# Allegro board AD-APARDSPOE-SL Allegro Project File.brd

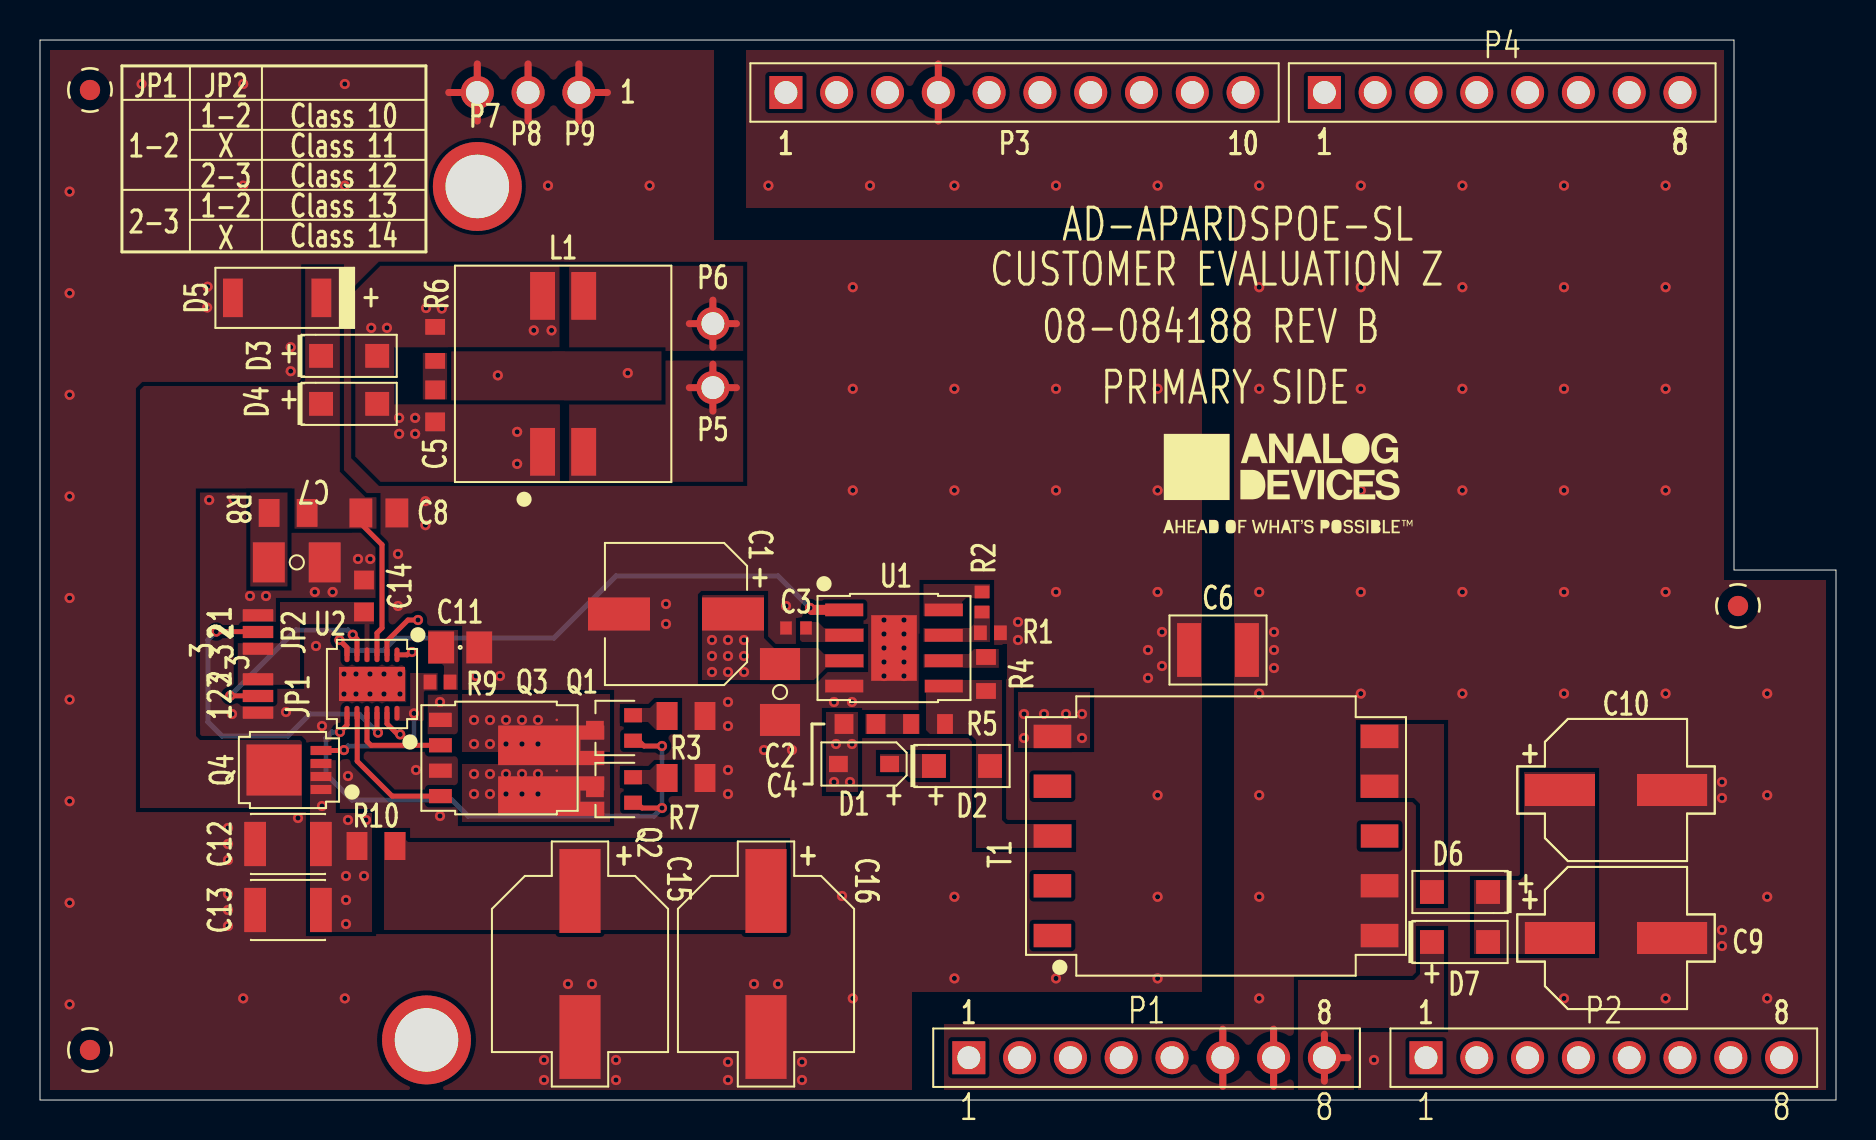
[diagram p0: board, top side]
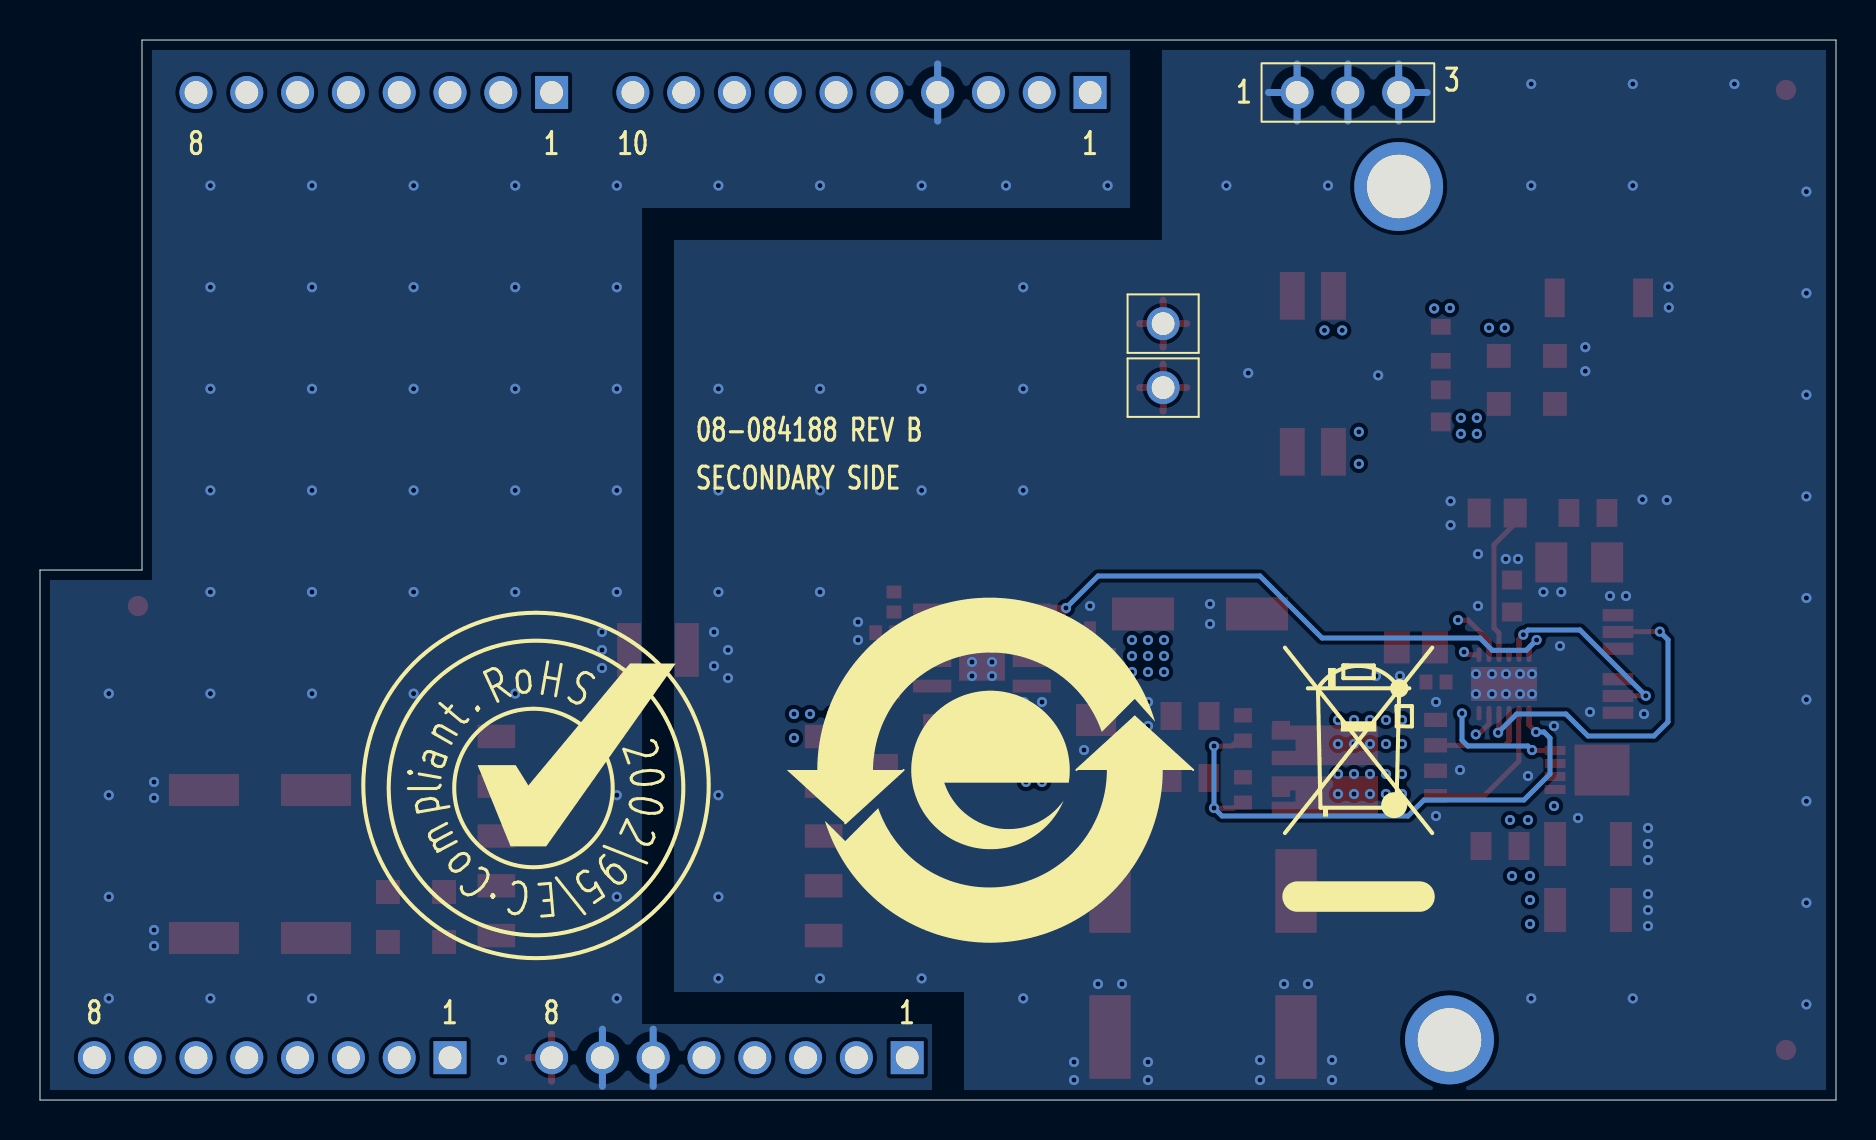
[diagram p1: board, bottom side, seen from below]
Outline 89.8 x 53 mm; copper layers: TOP, L2_GND, L3_PWR, BOTTOM. Coordinates in mm from the lower left corner of the outline.
Outline path: 0,53 84.7,53 84.7,26.5 89.8,26.5 89.8,0 0,0 0,53

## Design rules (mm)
constraint set DEFAULT: min track width 0.203

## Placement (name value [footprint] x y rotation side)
C1  22UF  [CPLSMSQ260H315]  31.8 24.3 180 top
C2  10UF  [C1206H71]  37 20.4 270 top
C3  1uF  [C0402]  37.8 23.6 180 top
C4  220pF  [C0603]  41 18.8 0 top
C5  0.047UF  [C0603]  19.76 34.71 270 top
C6  4.7NF  [C1210H67]  58.9 22.5 0 top
C7  150NF  [C1206H71]  12.84 26.88 0 top
C8  0.047uF  [C0805]  16.94 29.35 0 top
C9  220UF  [CPLSMSQ260H303]  78.8 8.1 0 top
C10  220UF  [CPLSMSQ260H303]  78.8 15.5 0 top
C11  0.022UF  [C0805H60]  21.01 22.63 180 top
C12  4.7uF  [C1210H87]  12.4 12.8 180 top
C13  4.7uF  [C1210H87]  12.4 9.5 180 top
C14  2.2uF  [C0603]  16.2 25.2 270 top
C15  33UF  [CPLSMSQ327H413]  27 6.8 270 top
C16  33UF  [CPLSMSQ327H413]  36.3 6.8 270 top
D1  BZX384-B51  [SOD323-2]  41.2 16.8 180 top
D2  PMEG10020AELRX  [SOD123F]  46.1 16.7 0 top
D3  PMEG10020AELRX  [SOD123F]  15.46 37.21 0 top
D4  PMEG10020AELRX  [SOD123F]  15.46 34.81 0 top
D5  PTVS58VP1UTP  [SOD128]  11.86 40.11 180 top
D6  PMEG10020AELRX  [SOD123F]  71 10.4 180 top
D7  PMEG10020AELRX  [SOD123F]  71 7.9 0 top
JP1  3PIN_SOLDER_JUMPER  [JPRSLD03]  10.9 20.2 90 top
JP2  3PIN_SOLDER_JUMPER  [JPRSLD03]  10.9 23.4 270 top
L1  68UH  [LSMSQ406H197]  26.16 36.31 90 top
NOREF  -  []  33.16 0 90 top
NOREF#2  -  [unnamed#2]  21.87 45.68 0 top
NOREF#3  -  [unnamed#2]  84.9 24.7 0 top
NOREF#4  -  [unnamed#2]  19.33 3 0 top
NOREF#5  -  [unnamed#2]  2.5 2.5 0 top
NOREF#6  -  []  -82.6 -106.1 0 top
NOREF#7  -  []  162.5 76.5 0 top
NOREF#8  -  []  62.1 30.8 0 top
NOREF#9  -  [unnamed#2]  2.5 50.5 0 top
NOREF#10  -  []  118 237.1 0 top
NOREF#11  -  []  89.8 0 90 top
NOREF#12  -  []  -82.6 -104.4 0 top
NOREF#13  -  []  -83 -106.1 0 top
NOREF#14  -  []  84.7 53 180 top
NOREF#15  -  []  0 49.82 0 top
NOREF#16  -  []  47.9 64 0 top
NOREF#17  -  []  0 53 270 top
NOREF#18  -  []  0 0 0 top
NOREF#19  -  []  65 15.6 180 bottom
NOREF#20  -  []  14.6 26.3 180 bottom
NOREF#21  -  []  42.3 16.5 180 bottom
NOREF#22  -  []  42.7 38.5 270 bottom
P1  ESQ-108-24-T-S  [CNTHFHDR1X8L820W95H545]  46.44 2.12 0 top
P2  ESQ-108-24-T-S  [CNTHFHDR1X8L820W95H545]  69.3 2.12 0 top
P3  ESQ-110-24-T-S  [CNTHFHDR1X10L1020W95H545]  37.3 50.38 0 top
P4  ESQ-108-24-T-S  [CNTHFHDR1X8L820W95H545]  64.22 50.38 0 top
P5  SSQ-101-01-T-S  [CNTHFHDR1X1L120W95H340]  33.64 35.62 180 bottom
P6  SSQ-101-01-T-S  [CNTHFHDR1X1L120W95H340]  33.64 38.82 180 bottom
P7  SSQ-101-01-T-S  [CNTHFHDR1X1L120W95H340]  21.87 50.38 180 bottom
P8  SSQ-101-01-T-S  [CNTHFHDR1X1L120W95H340]  24.41 50.38 180 bottom
P9  SSQ-101-01-T-S  [CNTHFHDR1X1L120W95H340]  26.95 50.38 180 bottom
Q1  BSS123WQ-7-F  [SOT323]  28.7 18.6 90 top
Q2  BSS123WQ-7-F  [SOT323]  28.7 15.5 90 top
Q3  BUK9K29-100E,115  [SOT1205]  23.3 17.1 270 top
Q4  PSMN075-100MSEX  [SOT1210]  12.4 16.5 90 top
R1  10K  [R0402]  47.52 23.36 0 top
R2  100K  [R0402]  47.1 24.9 90 top
R3  3.3  [R0805]  32.3 19.2 0 top
R4  261K  [R0603]  47.3 21.3 270 top
R5  100  [R0603]  44.4 18.8 0 top
R6  100  [R0603]  19.76 37.81 270 top
R7  3.3  [R0805]  32.3 16.1 0 top
R8  40.2  [R0805]  12.41 29.35 180 top
R9  10K  [R0402]  20 20.9 180 top
R10  3.3  [R0805]  16.8 12.7 0 top
T1  750315126  [TSMSQ530H505]  58.8 13.2 90 top
U1  LT8304IS8E#PBF  [SO8NB_PAD3_27X2_28-05-08-1857]  42.7 22.6 270 top
U2  LTC9111RDE#PBF  [DFN12_4X3_PAD3_3X1_7-05-08-1695]  16.6 20.8 180 top

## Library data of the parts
C1 = CAPP: Tolerance: 20; User Part Number: UPN; alternate symbols: (); tolerance: 20
C2 C7 = CAP: Tolerance: 10; User Part Number: UPN; alternate symbols: (C1206H71L); tolerance: 10
C3 = CAP: User Part Number: UPN; Tolerance: 10; alternate symbols: (C0402L); tolerance: 10
C4 = CAP: User Part Number: UPN; Tolerance: 5; alternate symbols: (C0603L); tolerance: 5
C5 C14 = CAP: User Part Number: UPN; Tolerance: 10; alternate symbols: (C0603L); tolerance: 10
C6 C12 C13 = CAP: Tolerance: 10; User Part Number: UPN; alternate symbols: (); tolerance: 10
C8 = CAP: User Part Number: UPN; Tolerance: 10; alternate symbols: (C0805L); tolerance: 10
C9 C10 C15 C16 = CAPP: User Part Number: UPN; Tolerance: 20; alternate symbols: (); tolerance: 20
C11 = CAP: Tolerance: 5; User Part Number: UPN; alternate symbols: (); tolerance: 5
D1 = DIOZNR: Tolerance: 2; User Part Number: UPN; alternate symbols: (); tolerance: 2
D2-D4 D6 D7 = DIOSCHOTTKY: Tolerance: N/A; User Part Number: UPN; alternate symbols: (); tolerance: N/A
D5 = DIOZNR: User Part Number: UPN; Tolerance: N/A; alternate symbols: (); tolerance: N/A
JP1 JP2 = NC3P_JMPR: Tolerance: N/A; User Part Number: UPN; alternate symbols: (); tolerance: N/A
L1 = IND_4P_V4: User Part Number: UPN; Tolerance: 20; alternate symbols: (); tolerance: 20
P1 P2 P4 = CN8P_A: User Part Number: UPN; Tolerance: N/A; alternate symbols: (); tolerance: N/A
P3 = CN10P: User Part Number: UPN; Tolerance: N/A; alternate symbols: (); tolerance: N/A
P5-P9 = CN1P: User Part Number: UPN; Tolerance: N/A; alternate symbols: (); tolerance: N/A
Q1 Q2 = TRANNMOSFET_V8: User Part Number: UPN; Tolerance: N/A; alternate symbols: (); tolerance: N/A
Q3 = TRANNMOSFET_DUAL: Tolerance: N/A; User Part Number: UPN; alternate symbols: (); tolerance: N/A
Q4 = TRANNMOSFET_V15: Tolerance: N/A; User Part Number: UPN; alternate symbols: (); tolerance: N/A
R1 R9 = RES: User Part Number: UPN; Tolerance: 1; alternate symbols: (R0402L,R0402L_ALT); tolerance: 1
R2 = RES: User Part Number: UPN; Tolerance: 5; alternate symbols: (R0402L); tolerance: 5
R3 R7 R10 = RES: User Part Number: UPN; Tolerance: 5; alternate symbols: (R0805L); tolerance: 5
R4-R6 = RES: User Part Number: UPN; Tolerance: 1; alternate symbols: (R0603L); tolerance: 1
R8 = RES: User Part Number: UPN; Tolerance: 1; alternate symbols: (R0805L); tolerance: 1
T1 = XFMR10P_V16: User Part Number: UPN; Tolerance: N/A; alternate symbols: (); tolerance: N/A
U1 = ADLT8304: Tolerance: N/A; User Part Number: UPN; alternate symbols: (); tolerance: N/A
U2 = ADLTC9111_V2: User Part Number: UPN; Tolerance: N/A; alternate symbols: (); tolerance: N/A

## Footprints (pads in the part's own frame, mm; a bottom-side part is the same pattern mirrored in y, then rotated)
C0402
  rect 0.584x0.66 smd: 1(-0.5,0) 2(0.5,0)
C0603
  rect 0.94x0.991 smd: 1(-0.8,0) 2(0.8,0)
C0805
  rect 1.143x1.448 smd: 1(-0.9,0) 2(0.9,0)
C0805H60
  rect 1.295x1.6 smd: 1(-0.953,0) 2(0.953,0)
C1206H71
  rect 1.6x2.007 smd: 1(-1.397,0) 2(1.397,0)
C1210H67
  rect 1.194x2.692 smd: 1(-1.448,0) 2(1.448,0)
C1210H87
  rect 1.092x2.21 smd: 1(-1.646,0) 2(1.646,0)
CNTHFHDR1X1L120W95H340
  round 1.651 hole 1.143: 1(0,0)
CNTHFHDR1X8L820W95H545
  rect 1.651x1.651 hole 1.143: 1(0,0)
  round 1.651 hole 1.143: 2(2.54,0) 3(5.08,0) 4(7.62,0) 5(10.16,0) 6(12.7,0) 7(15.24,0) 8(17.78,0)
CNTHFHDR1X10L1020W95H545
  rect 1.651x1.651 hole 1.143: 1(0,0)
  round 1.651 hole 1.143: 2(2.54,0) 3(5.08,0) 4(7.62,0) 5(10.16,0) 6(12.7,0) 7(15.24,0) 8(17.78,0) 9(20.32,0) 10(22.86,0)
CPLSMSQ260H303
  rect 3.505x1.6 smd: N(2.803,0) P(-2.803,0)
CPLSMSQ260H315
  rect 3.099x1.651 smd: N(2.85,0) P(-2.85,0)
CPLSMSQ327H413
  rect 4.191x2.057 smd: N(3.65,0) P(-3.65,0)
DFN12_4X3_PAD3_3X1_7-05-08-1695
  oval 0.254x0.737 smd: 1(-1.25,-1.46) 2(-0.75,-1.46) 3(-0.25,-1.46) 4(0.25,-1.46) 5(0.75,-1.46) 6(1.25,-1.46) 7(1.25,1.46) 8(0.75,1.46) 9(0.25,1.46) 10(-0.25,1.46) 11(-0.75,1.46) 12(-1.25,1.46)
  rect 3.302x1.702 smd: 13(0,0)
JPRSLD03
  rect 0.61x1.524 smd: 1(-0.838,0) 2(0,0) 3(0.838,0)
LSMSQ406H197
  rect 2.388x1.245 smd: 1(-3.899,1.029) 2(-3.899,-1.029) 3(3.899,-1.029) 4(3.899,1.029)
R0402
  rect 0.635x0.737 smd: 1(-0.5,0) 2(0.5,0)
R0603
  rect 0.787x0.991 smd: 1(-0.85,0) 2(0.85,0)
R0805
  rect 1.041x1.397 smd: 1(-0.95,0) 2(0.95,0)
SO8NB_PAD3_27X2_28-05-08-1857
  rect 0.635x1.905 smd: 1(-1.905,-2.49) 2(-0.635,-2.49) 3(0.635,-2.49) 4(1.905,-2.49) 5(1.905,2.49) 6(0.635,2.49) 7(-0.635,2.49) 8(-1.905,2.49)
  rect 3.277x2.286 smd: 9(0,0)
SOD123F
  rect 1.194x1.194 smd: A(1.403,0) C(-1.403,0)
SOD128
  rect 0.991x1.93 smd: A(2.21,0) C(-2.21,0)
SOD323-2
  rect 0.94x0.813 smd: A(1.28,0) C(-1.28,0)
SOT323
  rect 0.711x0.889 smd: 1(-0.635,-0.953) 2(0.635,-0.953) 3(0,0.953)
SOT1205
  rect 0.711x1.143 smd: 1(-1.905,-3.279) 2(-0.635,-3.279) 3(0.635,-3.279) 4(1.905,-3.279)
  custom 0.495x0.495 smd: 5(1.905,2.26) 7(-0.635,2.26)
  round 0.127 smd: 6(0.635,2.54) 8(-1.905,2.54)
SOT1210
  rect 0.457x1.041 smd: 1(-0.975,-1.65) 2(-0.325,-1.65) 3(0.325,-1.65) 4(0.975,-1.65)
  round 0.127 smd: 5(0.975,1.65) 6(0.325,1.65) 7(-0.325,1.65) 8(-0.975,1.65)
TSMSQ530H505
  rect 1.168x1.88 smd: 1(-4.978,8.179) 2(-2.489,8.179) 3(0,8.179) 4(2.489,8.179) 5(4.978,8.179) 6(4.978,-8.179) 7(2.489,-8.179) 8(0,-8.179) 9(-2.489,-8.179) 10(-4.978,-8.179)
unnamed#2
  round 4.445 hole 3.175 unplated: (0,0)

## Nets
12V_ISO: D7.C P1.8(N8)
DGND: C6.2(N2) C9.N(N2) C10.N(N2) P1.6 P1.7 P3.4 T1.9 T1.10
GND: C1.N(N2) C2.2(N2) C3.2(N2) C6.1 C7.2(N2) C8.2(N2) C11.1 C12.2(N2) C13.2(N2) C14.1 C15.N(N2) C16.N(N2) D5.A(P) JP1.1 JP2.1 P7.1(N1) P8.1(N1) P9.1(N1) Q3.1 Q3.3(S) R1.2(N2) R3.2(N2) R7.2(N2) U1.4 U1.9 U2.13
_N151: C5.1 R6.2(N2)
_N152: C7.1 R8.2(N2)
_N153: C11.2(N2) R9.1
_N154: C15.P C16.P R10.2(N2)
_N155: Q1.2(S) R3.1
_N156: Q2.2(S) R7.1
_N157: JP1.2(COM) U2.5
_N158: JP2.2(COM) U2.10
_N224: R1.1 R2.1 U1.7
_N263: L1.2 P5.1(N1)
_N264: L1.3 P6.1(N1)
_N270: D6.A(P) T1.6 T1.7
_N709: D1.C D2.C
_N710: C4.2(N2) R5.1
_N711: R4.1 U1.6
_N712: D2.A(P) R4.2(N2) R5.2(N2) T1.3 U1.5
_N713: C3.1 U1.2
_N721: C9.P C10.P D6.C D7.A(P)
LGATE1: Q3.2 U2.9
LGATE2: Q3.4 U2.8
LT8304_EN: U1.1 U2.6
LTC_GATE: Q4.4 R9.2(N2) U2.12
LTC_IN: C8.1 D3.C D4.C D5.C Q4.5 Q4.6 Q4.7 Q4.8 R8.1 U2.3
LTC_OUT: C1.P C2.1 C4.1 C12.1 C13.1 D1.A(P) Q4.1 Q4.2 Q4.3(S3) R10.1 T1.5 U1.3(VIN) U2.11
POWER_N: C5.2(N2) D4.A(P) L1.1 Q2.3 Q3.5 Q3.6 U2.2
POWER_P: D3.A(P) L1.4(N4) Q1.3 Q3.7 Q3.8 R6.1 U2.1
SCCP: Q1.1 Q2.1 U2.7
STBY: C14.2(N2) JP1.3 JP2.3 U2.4(STBY)
TC: R2.2(N2) U1.8

Pads without a net: P1 1 2 3 4 5; P2 1 2 3 4 5 6 7 8; P3 1 2 3 5 6 7 8 9 10; P4 1 2 3 4 5 6 7 8; T1 1 2 4 8

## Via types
v1: diameter 0.508, hole 0.254, TOP to BOTTOM, 205 vias
v2: diameter 0.508, hole 0.264, TOP to BOTTOM, 40 vias

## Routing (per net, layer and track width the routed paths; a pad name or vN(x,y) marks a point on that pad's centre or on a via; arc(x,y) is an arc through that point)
12V_ISO: length 3.5
  TOP w0.35: P1.8 64.22,3.29 ; P1.8 65.4,2.12 ; P1.8 64.22,0.94
DGND: length 34.2
  TOP w0.35: 61.68,3.54 P1.7 61.68,0.69 ; 59.14,0.69 P1.6 59.14,3.54 ; 44.92,48.95 P3.4 44.92,51.8
  L2_GND w0.35: 44.92,48.95 P3.4 44.92,51.8 ; 59.14,0.69 P1.6 59.14,3.54 ; 61.68,3.54 P1.7 61.68,0.69
  L3_PWR w0.35: 44.92,51.8 P3.4 44.92,48.95 ; 61.68,0.69 P1.7 61.68,3.54 ; 59.14,0.69 P1.6 59.14,3.54
  BOTTOM w0.35: 59.14,0.69 P1.6 59.14,3.54 ; 44.92,51.8 P3.4 44.92,48.95 ; 61.68,3.54 P1.7 61.68,0.69
  vias: v1(36.42,45.72) v1(41.5,45.72) v1(45.72,45.72) v1(50.8,45.72) v1(55.88,45.72) v1(60.96,45.72) v1(60.96,40.64) v1(60.96,35.56) v1(60.96,30.48) v1(60.96,25.4) v1(60.96,20.32) v1(60.96,15.24) v1(60.96,10.16) v1(60.96,5.08) v1(61.7,23.4) v1(61.7,22.5) v1(61.7,21.6) v1(66.04,45.72) v1(66.04,40.64) v1(66.04,35.56) v1(66.04,30.48) v1(66.04,25.4) v1(66.04,20.32) v1(66.7,2) v1(71.12,45.72) v1(71.12,40.64) v1(71.12,35.56) v1(71.12,30.48) v1(71.12,25.4) v1(71.12,20.32) v1(76.2,45.72) v1(76.2,40.64) v1(76.2,35.56) v1(76.2,30.48) v1(76.2,25.4) v1(76.2,20.32) v1(76.2,5.08) v1(81.28,45.72) v1(81.28,40.64) v1(81.28,35.56) v1(81.28,30.48) v1(81.28,25.4) v1(81.28,20.32) v1(81.28,5.08) v1(84.1,15.9) v1(84.1,15.1) v1(84.1,8.5) v1(84.1,7.7) v1(86.36,20.32) v1(86.36,15.24) v1(86.36,10.16) v1(86.36,5.08)
GND: length 45.6
  TOP w0.35: P7.1 21.87,51.8 ; P7.1 21.87,48.95 ; P7.1 20.44,50.38 ; P9.1 28.37,50.38 ; P9.1 26.95,48.95 ; P9.1 26.95,51.8 ; 24.41,48.95 P8.1 24.41,51.8
  L2_GND w0.35: 26.95,48.95 P9.1 ; P9.1 28.37,50.38 ; P9.1 26.95,51.8 ; 21.87,48.95 P7.1 ; P7.1 20.44,50.38 ; P7.1 21.87,51.8 ; 24.41,48.95 P8.1 24.41,51.8
  L3_PWR w0.35: 21.87,48.95 P7.1 ; P7.1 20.44,50.38 ; P7.1 21.87,51.8 ; 26.95,48.95 P9.1 ; P9.1 26.95,51.8 ; P9.1 28.37,50.38 ; 24.41,51.8 P8.1 24.41,48.95
  BOTTOM w0.35: 24.41,51.8 P8.1 24.41,48.95 ; P7.1 21.87,51.8 ; P7.1 21.87,48.95 ; P7.1 20.44,50.38 ; 26.95,48.95 P9.1 ; P9.1 28.37,50.38 ; P9.1 26.95,51.8
  vias: v1(1.48,45.42) v1(1.48,40.34) v1(1.48,35.26) v1(1.48,30.18) v1(1.48,25.1) v1(1.48,20.02) v1(1.48,14.94) v1(1.48,9.86) v1(1.48,4.78) v1(5.08,50.8) v1(8.38,40.67) v1(8.36,39.62) v1(8.46,30) v1(9.4,13.6) v1(9.4,12.8) v1(9.4,12) v1(9.4,10.3) v1(9.4,9.5) v1(9.4,8.7) v1(9.6,19.3) v1(9.68,30.02) v1(10.16,50.8) v1(10.16,45.72) v1(10.16,5.08) v1(10.5,25.2) v1(11.3,25.2) v1(12.3,19.4) v1(12.54,37.64) v1(12.54,36.44) v1(12.9,14.1) v1(13.74,25.4) v1(13.8,22.7) v1(14.1,18.7) v1(14.63,25.4) v1(15.24,50.8) v1(15.24,45.72) v1(15.24,5.08) v1(15.4,16.2) v1(15.9,27.05) v1(16.51,27.05) v1(17.9,27.3) v1(17.9,24.7) v1(18.8,16.5) v1(19.27,29.94) v1(19.27,28.74) v1(20,19.9) v1(20,14.2) v1(21.8,21.2) v1(22.89,36.23) v1(23,21.2) v1(25.2,2) v1(25.2,1) v1(25.4,45.72) v1(26.4,5.8) v1(27.6,5.8) v1(28.8,2) v1(28.8,1) v1(29.39,36.35) v1(30.48,45.72) v1(31.3,24.8) v1(31.3,23.8) v1(34.4,19.9) v1(34.4,18.7) v1(34.4,16.5) v1(34.4,15.3) v1(34.4,1.9) v1(34.4,1) v1(35.7,5.8) v1(36.2,17.5) v1(36.9,5.8) v1(37.3,24.7) v1(37.6,17.5) v1(38.1,1.9) v1(38.1,1) v1(39.7,19.9) v1(40.1,10.2) v1(40.64,40.64) v1(40.64,35.56) v1(40.64,30.48) v1(40.6,19.9) v1(40.64,5.08) v1(45.72,35.56) v1(45.72,30.48) v1(45.72,10.16) v1(45.72,6.08) v1(48.9,23.9) v1(48.9,23) v1(50.8,35.56) v1(50.8,30.48) v1(50.8,25.4) v1(50.8,6.08) v1(55.4,22.5) v1(55.4,21.1) v1(55.88,35.56) v1(55.88,30.48) v1(55.88,25.4) v1(55.88,15.24) v1(55.88,10.16) v1(55.88,6.08) v1(56.1,23.4) v1(56.1,21.7) v2(15.2,21.3) v2(15.2,20.3) v2(15.8,21.3) v2(15.8,20.3) v2(16.5,21.3) v2(16.5,20.3) v2(17.2,21.3) v2(17.2,20.3) v2(18,21.3) v2(18,20.3) v2(42.2,24) v2(42.2,23.3) v2(42.2,22.6) v2(42.2,21.9) v2(42.2,21.2) v2(43.2,24) v2(43.2,23.3) v2(43.2,22.6) v2(43.2,21.9) v2(43.2,21.2)
_N157: length 10.1
  TOP w0.25: JP1.2 10.89,20.21 v1(9.51,20.21) ; U2.5 15.85,23.05 v1(15.63,23.27)
  BOTTOM w0.25: v1(9.51,20.21) 12.8,23.5 15.4,23.5 v1(15.63,23.27)
_N158: length 17.4
  TOP w0.25: v1(16.9,18.37) 16.85,18.42 U2.10 ; v1(8.81,23.42) 10.88,23.42 JP2.2
  BOTTOM w0.25: v1(16.9,18.37) 15.97,19.3 13.5,19.3 12.4,18.2 9.1,18.2 8.4,18.9 8.4,23.01 v1(8.81,23.42)
_N263: length 4.7
  TOP w0.35: P5.1 34.82,35.62 ; P5.1 32.47,35.62 ; P5.1 33.64,34.44 ; P5.1 33.64,36.79
_N264: length 4.7
  TOP w0.35: P6.1 33.64,39.99 ; P6.1 32.47,38.82 ; P6.1 34.82,38.82 ; P6.1 33.64,37.64
LGATE1: length 5.2
  TOP w0.25: U2.9 16.35,17.93 16.55,17.73 Q3.2
LGATE2: length 7.3
  TOP w0.25: Q3.4 17.61,15.2 15.86,16.94 15.86,19.33 U2.8
LT8304_EN: length 28.6
  TOP w0.25: U2.6 15.35,22.62 v1(14.97,23)
  TOP w0.5: v1(38.5,24.6) 38.59,24.5 40.21,24.5
  BOTTOM w0.25: v1(38.5,24.6) 36.9,26.2 28.8,26.2 25.7,23.1 17.8,23.1 17.19,22.49 15.48,22.49 v1(14.97,23)
LTC_GATE: length 6.2
  TOP w0.25: v1(15.2,17.5) 15.18,17.48 Q4.4
  BOTTOM w0.25: v1(18.7,19.33) 18.7,17.99 18.41,17.7 15.4,17.7 v1(15.2,17.5)
LTC_IN: length 7.6
  TOP w0.25: U2.3 16.85,23.35 17.1,23.6 17.1,27.76 16.04,28.82 C8.1
LTC_OUT: length 1.4
  TOP w0.25: v1(18.01,18.28) 17.98,18.25 17.91,18.25 17.35,18.81 U2.11
  vias: v1(14.1,14.7) v1(15.3,11.2) v1(15.3,10) v1(15.3,8.8) v1(15.4,14) v1(16.2,11.2) v1(16.3,14) v1(33.6,23) v1(33.6,22.2) v1(33.6,21.4) v1(34.4,23) v1(34.4,22.2) v1(34.4,21.4) v1(35.2,23) v1(35.2,22.2) v1(35.2,21.4) v1(39.7,15.9) v1(39.8,17.8) v1(40.5,15.9) v1(40.6,17.8) v1(49.2,19.3) v1(49.2,18.1) v1(50.2,19.3) v1(51.3,19.3) v1(52.1,19.3) v1(52.1,18.1)
POWER_N: length 2.7
  TOP w0.25: v1(18.9,24) 18.4,24 17.35,22.95 U2.2
  vias: v1(17.96,34.11) v1(17.96,33.31) v1(18.76,34.11) v1(18.76,33.31) v1(23.86,33.41) v1(23.86,31.81) v2(21.7,16.3) v2(21.7,15.3) v2(22.5,16.3) v2(22.5,15.3) v2(23.3,16.3) v2(23.3,15.3) v2(24.1,16.3) v2(24.1,15.3) v2(24.9,16.3) v2(24.9,15.3)
POWER_P: length 0.8
  TOP w0.25: v1(18.6,22.4) 18.5,22.4 18.36,22.26 U2.1
  vias: v1(16.56,38.61) v1(17.35,38.61) v1(19.3,39.6) v1(20.09,39.57) v1(24.69,38.48) v1(25.58,38.48) v2(21.7,19) v2(21.7,17.8) v2(22.5,19) v2(22.5,17.8) v2(23.3,19) v2(23.3,17.8) v2(24.1,19) v2(24.1,17.8) v2(24.9,19) v2(24.9,17.8)
SCCP: length 27.8
  TOP w0.25: Q1.1 29.93,17.96 30.2,17.7 v1(31.1,17.7) ; Q2.1 29.84,14.87 30.1,14.6 v1(31.1,14.6) ; v1(15,18.4) 15.35,18.75 U2.7
  BOTTOM w0.25: v1(15,18.4) 14.6,18.4 14.3,18.1 14.3,16.3 15.6,15 20.6,15 21.4,14.2 30.7,14.2 v1(31.1,14.6) v1(31.1,17.7)

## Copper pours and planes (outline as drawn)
12V_ISO on TOP: 62.9,6 62.9,0.5 65.7,0.5 65.7,3.6 70.2,3.6 70.2,8.5 69,8.5 69,6.3 68.7,6
DGND on TOP, BOTTOM, L2_GND, L3_PWR: 44.1,52.5 84.2,52.5 84.2,26 89.3,26 89.3,0.5 57.81,0.5 45.2,0.5 45.2,3.8 59.7,3.8 59.7,44.6 35.3,44.6 35.3,52.5
GND on TOP: 0.5,52.5 33.7,52.5 33.7,43 58.1,43 58.1,5.4 43.6,5.4 43.6,0.5 20.25,0.5 20.15,0.58 20.22,0.7 21.36,1.61 21.8,3 19.33,5.48 16.85,3 17.29,1.61 18.44,0.7 18.5,0.58 18.4,0.5 0.5,0.5 ; 6 cut-outs
GND on BOTTOM, L2_GND, L3_PWR: 0.5,52.5 33.7,52.5 33.7,43 58.1,43 58.1,5.4 43.6,5.4 43.6,0.5 20.25,0.5 20.15,0.58 20.22,0.7 21.36,1.61 21.8,3 19.33,5.48 16.85,3 17.29,1.61 18.44,0.7 18.5,0.58 18.4,0.5 0.5,0.5
_N151 on TOP: 19.14,37.35 19.14,35.02 20.35,35.02 20.35,37.35
_N152 on TOP: 10.52,30.38 10.52,25.68 12.37,25.68 12.37,30.38
_N153 on TOP: 20.9,20.5 20.9,23.5 19.4,23.5 19.4,21.8 20.1,21.8 20.2,21.7 20.2,20.5
_N154 on TOP: 18.3,13.4 17.2,13.4 17.2,8.5 37.3,8.5 37.3,12.9 18.4,12.9 18.3,13
_N155 on TOP: 29.2,18.9 30.4,18.9 30.8,18.5 31.9,18.5 31.9,19.9 30.8,19.9 30.5,19.6 29.2,19.6
_N156 on TOP: 29.2,16.5 29.2,15.8 30.4,15.8 30.8,15.4 31.9,15.4 31.9,16.8 30.8,16.8 30.5,16.5
_N224 on TOP: 44.18,23.6 44.18,22.9 47.5,22.9 47.5,24.7 46.69,24.7 46.69,23.79 46.5,23.6
_N263 on TOP: 26.46,34.78 26.46,30.91 35.16,30.91 35.16,36.97 31.28,36.97 31.28,34.78
_N264 on TOP: 26.46,41.71 26.46,37.64 31.28,37.64 31.28,37.45 35.16,37.45 35.16,41.71
_N270 on TOP: 68.7,15.1 69,14.8 69,9.8 70.2,9.8 70.2,18.8 66,18.8 66,15.1
_N709 on TOP: 42,17.3 42,16.4 43.2,16.4 43.5,16.1 45.3,16.1 45.3,17.3
_N710 on TOP: 41.27,19.3 41.27,18.3 43.99,18.3 43.99,19.3
_N711 on TOP: 44.18,21.61 47.94,21.61 47.94,22.55 46.7,22.55 46.45,22.3 44.2,22.3 44.18,22.28
_N712 on TOP: 46.5,18.3 46.8,18 46.8,12.6 51.6,12.6 51.6,13.8 48.3,13.8 48.1,14 48.1,21 44.3,21 44.3,18.5 44.5,18.3
_N713 on TOP: 39.2,23.6 38.9,23.9 38,23.9 38,23 38.1,22.9 41.2,22.9 41.2,23.6
_N721 on TOP: 77.75,7.3 77.75,16.4 74.2,16.4 74.2,11.2 74,11 71.7,11 71.7,7.3
LTC_GATE on TOP: 17.73,18.96 17.73,19.69 18.51,19.69 18.51,21.35 19.88,21.35 19.88,20.47 19.26,20.47 19.19,20.4 19.19,19 19.15,18.96
LTC_IN on TOP (solid shape): 13.07,15.22 10.32,15.22 10.32,17.77 13.07,17.77
LTC_IN on TOP: 13.26,41.58 14.99,41.58 14.99,31.41 16.26,30.14 16.82,30.14 16.82,28.57 12.73,28.56 12.73,30.58 7.79,30.58 7.79,18.5 7.8,18.5 7.8,18.2 8,18 13,18 13.1,17.9 13.1,14.6 5,14.6 5,35.5 5.2,35.7 13,35.7 13.26,35.96
LTC_OUT on TOP: 48.9,20.4 48.9,17.6 52.5,17.6 52.5,20.4
LTC_OUT on TOP: 13.5,8.4 16.6,8.4 16.6,14.35 14.79,14.35 14.79,16.99 13.5,16.99
LTC_OUT on TOP: 39.3,19.4 39.3,15.4 40.9,15.4 40.9,19.4
LTC_OUT on TOP: 41.2,21.6 41.2,22.3 39.2,22.3 38.9,22.6 36.7,22.6 36.2,23.1 36.2,25.25 33.15,25.25 33.1,25.2 33.1,21 38.7,21 39.3,21.6
LTC_OUT on L3_PWR: 36.3,25.2 36.3,22.7 36.4,22.6 41.2,22.6 41.2,21.27 38.5,21.27 38.5,19.4 38.6,19.3 48.53,19.3 48.58,19.35 48.58,19.73 48.67,19.83 52.53,19.83 52.6,19.76 52.6,16.7 40.9,16.7 40.9,8.3 13.4,8.3 13.4,16.99 16.49,16.99 17.4,17.9 17.4,18.6 18.33,18.6 18.33,13.87 19.17,13.03 32.43,13.03 33.1,13.7 33.1,25.2
POWER_N on TOP: 15.76,35.88 15.76,32.18 17.03,30.91 26,30.91 26,34.78 17.72,34.78 17.72,35.88
POWER_N on TOP: 21.1,16.8 21.1,13.9 28.5,13.9 28.5,16.8
POWER_N on L3_PWR: 17.63,34.78 25.99,34.78 25.99,32.18 28.26,29.91 28.26,15.28 27.27,14.29 21.01,14.29 21.01,16.8 26.3,16.8 26.8,17.3 26.8,22.03 25.53,23.3 18.9,23.3 17.63,24.57
POWER_P on TOP: 21.1,17.4 28.5,17.4 28.5,20.3 21.1,20.3
POWER_P on TOP: 15.75,40.44 15.75,36.13 17.71,36.13 17.71,37.64 25.98,37.64 25.98,37.94 25.98,41.71 17.02,41.71
POWER_P on L3_PWR: 14.3,39.93 27.7,39.93 27.7,37.66 17.4,37.66 17.4,27.36 17.4,27.24 17.4,24.76 17.4,24.64 17.4,23.34 17.68,23.06 25.26,23.06 26.55,21.78 26.55,20.3 26.55,17.4 26.55,17.4 21.1,17.4 21,17.4 21,17.4 21,20.9 19.9,22 14.4,22 14.3,22.1 14.3,22.64 14.3,22.76
STBY on TOP: 12,22.84 12,24.9 16.7,24.9 16.7,23.79 16.47,23.79 16.47,21.9 16.23,21.9 16.23,23.79 13,23.79 13,20.76 9.89,20.76 9.89,22.84
TC on TOP: 44.18,25.8 44.18,24.2 46.1,24.2 46.1,24.9 46.3,25.1 47.5,25.1 47.5,25.8

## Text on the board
Ref Des/Silkscreen Bottom: 08-084188 REV B | SECONDARY SIDE | 3 | 1
User.Comments: 4.   JUMPER SHORTED: | JP2: PIN2 & PIN 3 | JP1: PIN1 & PIN 2
Ref Des/Assembly Top: 3 | 1 | JP1
Ref Des/Silkscreen Top: + | 1-2 | 2-3 | JP1 | JP2 | X | Class 10 | Class 11 | Class 12 | Class 13 | Class 14 | 1 | CUSTOMER EVALUATION Z | 08-084188 REV B | AD-APARDSPOE-SL | PRIMARY SIDE
XSECTION_CHART: *  SURFACE | L1 TOP CONDUCTOR | *  DIELECTRIC | L2 LAYER2 PLANE | L3 LAYER3 PLANE | L4 BOTTOM CONDUCTOR | DESIGN CROSS SECTION CHART | ___________________________ | TOTAL THICKNESS 1.666 MM | 1-4
PAGE_OUTLINE: B | ECR-125794 | 14MAY25 | K. ARON
DIMENSION: (REF) | DIA MAX | SEE NOTE 27
User.10: L2 Internal GND | 08-      -07
User.11: L3 Internal GND | 08-      -08
User.12: FAB NOTES REVISION: NOVEMBER 21 2022 | 8.   IMPEDANCE REQUIREMENTS: IF NO STACKUP IS DEFINED, THE VENDOR IS ALLOWED TO ADJUST THE DIELECTRIC | 13.  PLATING SPECIFICATION: | 1.   DIMENSIONS ARE IN INCHES (EXCEPT WHERE NOTED). | ALL DOCUMENTS & SPECIFICATIONS REFERRED TO BELOW SHOULD BE THE LATEST REVISIONS. | 2.  BOARD MATERIAL:(USE CHECKED ITEMS) | 3.   ALL LAMINATES & BONDING MATERIALS SHOULD BE SELECTED FROM IPC-4101 OR IPC-4103,(TG>170 DEGC TD>300 DEGC) | 4.   REFER TO IPC-6010 SERIES, CLASS 2 FOR FABRICATION. | 5.   REFER TO LAMINATION DIAGRAM FOR OVERALL BOARD THICKNESS, TOLERANCE APPLIES AFTER ALL LAMINATION AND PLATING | 6.   BOW & TWIST NOT TO EXCEED 0.0075 INCHES (0.75%) PER LINEAR INCH AND SHOULD BE MEASURED PER IPC-TM-650, METHOD 2.4.22. | 7.   ACCEPTABILITY PER ADI SPECIFICATION TST00115. | 9.   FILLET OPTIONS TO ENHANCE RELIABILITY AT PAD JUNCTIONS WHERE SPACING PERMITS. | 10.  THIEVING: | 11.  LAYER TO LAYER REGISTRATION SHALL BE WITHIN 0.003 INCHES. | 12.  DRILL SIZES ARE FINISHED HOLE SIZES. ALL HOLES SHALL BE LOCATED WITHIN 0.005 INCHES DTP, | 14.  SURFACE FINISH: | 15.  SOLDERMASK: | 16.  APPLY SILKSCREEN TO BOTH SIDES USING A NON-CONDUCTIVE, EPOXY BASED INK PER ARTWORK. | (X) WHITE | ( ) OTHER | PROCESSES. FINISHED THICKNESS MEASURED FROM TOP COPPER TO BOTTOM COPPER. | (X)  ISOLA 370HR OR EQUIVALENT | ( )  ISOLA-FR408HR OR EQUIVALENT | ( )  ISOLA IS410 | ( )  MEGTRON 6 | ( )  NELCO-4000-13 | ( )  ROGERS 4350B | ( ) ROGERS 3003 | ( ) ARLON 85N | ( ) EM370D | ( )  OTHER ________________________ | ( ) FILLETS ALLOWED | (X) FILLETS NOT ALLOWED | ( ) VENDOR MAY ADD THIEVING TO COMPENSATE FOR LOW COPPER DENSITY AREAS MAINTAINING A MINIMUM | ( ) VENDOR MAY NOT ADD THIEVING TO COMPENSATE FOR LOW COPPER DENSITY AREAS. | (X) LPI | ( ) OTHER_________ | COLOR | ( ) GREEN | (X) BLUE | HINDER PROPER SOLDER WICKING. BARREL RELIEF ON SOLDERMASK ALLOWED IN UNFILLED VIA IN PAD HOLES. | (X) REFER TO LAMINATION DIAGRAM FOR FINISHED COPPER WEIGHT/THICKNESS REQUIRMENTS | (X) IMMERSION GOLD (ENIG) 1.58-3.94 MICRO INCHES OVER 118-236 MICRO INCHES MIN. OF ELECTROLESS NICKEL PER IPC-4552 | ( ) OSP (ORGANIC SOLDERABILITY PRESERVATIVE) | ( ) IMMERSION SILVER | ( ) SOFT WIRE BONDABLE GOLD 30-50 MICRO INCHES OF SOFT WIRE | ( ) EDGE CONNECTOR FINGERS ARE TO BE PLATED WITH 100 MICRO-INCHES(.0001") OF LOW STRESS | THICKNESS & TRACE WIDTHS TO MEET THE IMPEDANCE REQUIREMENT. IF SPECIFIED, THE VENDOR MUST | TRACE WIDTH & SPACING THAT IMPACT THE REQUIREMENTS MUST HAVE WRITTEN APPROVAL FROM ADI. | MINIMUM BARREL PLATING OF 0.001 INCHES. PLATED HOLES SHALL NOT BE ROUGH OR IRREGULAR SO AS TO | SOLDERMASK OVER BARE COPPER OR BARE GOLD (BOTH SIDES) TO MEET IPC-SM-840. | IF PRESENT,DO NOT MODIFY SOLDERMASK DEFINED PADS (MASK OPENINGS LESS THAN COPPER PAD) WITHOUT APPROVAL. | MEET THE REQUIREMENTS LISTED IN THE IMPEDANCE TABLE. ANY ADJUSTMENT MADE TO THE DEFINED STACKUP, | UL FLAMMABILITY RATING 94V-0. BOARD MATERIAL & CONSTRUCTION SHALL MEET THE REQUIREMENTS OF UL796/UL796F. | BONDABLE GOLD OVER 100-150 MICRO INCHES OF NICKEL | NICKEL UNDER 30 MICRO-INCHES (.00003') OF GOLD | 0.100 INCH CLEARANCE FROM ALL COPPER FEATURES, | THE STARTING COPPER WEIGHT/THICKNESS CAN VARY AS LONG AS THE FINISHED COPPER | WEIGHT/THICKNESS IS NOT LESS THAN THE SPECIFIED VALUE. | UNLESS OTHERWISE SPECIFIED | HOMOGENOUS MATERIALS IN THIS BOARD SHALL BE COMPLAINT WITH THE EU DIRECTIVE 2002/95/EC | WORKMANSHIP SHALL CONFORM TO IPC-A-600, CLASS 2. | 21.  INTENTIONAL SHORTS: | 17.  FINAL ELECTRICAL TEST TO BE PERFORMED USING PROVIDED IPC-D-356A NETLIST OR ODB++ FORMAT FILE. | 22.  PEMNUTS: | 23.  MANUFACTURER TO ETCH/STAMP WITH PERMANENT NON-CONDUCTIVE INK | ON SECONDARY SIDE UNLESS OTHERWISE SPECIFIED: | 18.  A TIME DOMAIN REFLECTOMETER REPORT (TDR) FOR EACH IMPEDANCE CONTROLLED LAYER & A CERTIFICATE | 19.  IF PRESENT, ALL BLIND/BURIED VIAS WITH AN ASPECT RATIO <1:1 TO BE PLATED SHUT WITH COPPER WHEN | 20.  FOR VIA FILL INFORMATION REFER TO DRILL CHART: | 24. PANELIZATION: | 27.  SOLDERMASK PLUG ALL 0.264MM DRILLED VIAS. | 25.  MINIMUM DESIGN LINE WIDTH IS 0.250 MM. | 26.  MINIMUM DESIGN LINE SPACING IS 0.120 MM. | IS ACCEPTABLE, ALL OTHER INSTANCES MUST BE REPORTED. | IF AN INTENTIONAL SHORT REPORT IS SUPPLIED AND DOES NOT MATCH THE FAB DATA THEN | THE PCB SHALL HAVE A VERIFICATION STAMP. | ( )  NON-CONDUCTIVE EPOXY FILL ALL 0.XXXX INCHES DRILLED VIAS | ( )  COPPER FILL ALL 0.XXXX INCHES DRILLED VIAS | ( ) PEMNUTS TO BE INSTALLED BY FABRICATOR | ( ) PEMNUTS NOT TO BE INSTALLED BY FABRICATOR | ( ) NOT APPLICABLE | USED AS VIA-IN-PAD OR AS A STACKED VIA. BLIND/BURIED VIAS WITH AN ASPECT RATIO >1:1 TO BE FILLED | A. UL CODE-FLAMMABILITY RATING FOR THOSE APPROVED MATERIALS(IF APPLICABLE) | B. DATE CODE | C. LOT NUMBER | D. MANUFACTURER LOGO | BOARDS TO BE SHIPPED IN SINGULATED AFTER FABRICATION PROCESS | SMOOTHEN EDGES AND FREE FROM BURRS AFTER PANELIZATION | CAN'T BE PERFORMED BECAUSE THE TRACE LENGTH IS TOO SHORT ON THE OUTER LAYERS AT THE PIN ESCAPES | ADI APPROVAL IS REQUIRED. | OF COMPLIANCE SHALL BE PROVIDED BY VENDOR AT TIME OF SHIPMENT. INSTANCES WHERE TDR TESTING | WITH NON-CONDUCTIVE EPOXY. | NOTES: | TOOLING: | FINISH: | MATERIAL: | TESTING: | MISCELLANEOUS:
User.16: 08-      -07 | L2_GND
User.17: L3_PWR | 08-      -08
User.34: PER ECR-094468 | B | 28MAY20 | PD
User.36: PAGE 1 OF 5 | TOP SIDE VIEW | VIEW OF SILKSCREEN, PINS, VIAS, | ETCH AND REFERENCE INFORMATION. | TEMPLATE NOTES. | 01.COMPONENTS ARE PLACED ON THIS SIDE. | 02.CONNECTORS P1,P2.P4 & P5 ARE PLACED | ON THIS SIDE OF THE BOARD. | 03.IF THE BOARD NEEDS TO BE INCREASED | IT CAN BE INCREASED IN THE DIRECTION | OF THE ARROWS. | 04.THE BOARD IS SET-UP AS A 4 LAYER | BOARD. MAKE SURE ANY SUBSEQUENT CHANGES, | MANUAL OR AUTOMATIC, DO NOT RESULT IN | ANY UNINTENDED CONSEQUENCES. | 05.THE EXISTING ROUTING CAN BE ALTERED AS | IS ROUTED TO CLOSE THE NETS ON THE | TEMPLATE BOARD.
User.37: PAGE 2 OF 5 | BOTTTOM SIDE VIEW | VIEW OF SILKSCREEN, PINS, VIAS, | ETCH AND REFERENCE INFORMATION. | TEMPLATE NOTES. | 01.COMPONENTS ARE PLACED ON THIS SIDE. | 02.CONNECTORS P3 IS PLACED ON THIS SIDE. THE | OTHER CONNECTORS ARE SOLDERED THIS SIDE. | 03.THE TEMPLATE IS VIEWED LOOKING FROM THE | TOP SIDE OF THE BOARD. THE RESULT IS | THAT TEXT IS MIRRORED. | 04.THE BOARD IS SET-UP AS A 4 LAYER | BOARD. MAKE SURE ANY SUBSEQUENT CHANGES, | MANUAL OR AUTOMATIC, DO NOT RESULT IN | ANY UNINTENDED CONSEQUENCES.
User.38: PAGE 3 OF 5 | PCB FAB SHEET 1 | NCDRILL LEGEND, APPROPRIATE | DETAILS AND OUTLINE DIMENSION NOTES. | 01. EACH TIME THE NC DRILL LEGEND | IS RUN, THE HOLE CHART MUST BE | CHECKED TO ASSURE THE TOLERANCES | & NOTES CORRESPOND TO THE RIGHT | PADSTACKS.
User.39: PAGE 4 OF 5 | PCB FAB SHEET 2 | FABRICATION NOTES. ALTER DEPENDING ON THE | REQUIREMENTS OF THE DESIGN.
User.40: TEMPLATE REVISION HISTORY | TEMPLATE BOARDS FOR EVAL PROVIDE INFORMATION IN THE | 5-VIEW "PDF FORMAT" FOR EVAL ENGINEERING | REFERENCE; ALONG WITH EMBEDDED ALLEGRO | PROPERTIES FOR PCB DESIGN USE. | THEY MAINTAIN A SEPARATE TITLE BLOCK AND PART | NUMBER FOR REVISION TRACKING, INDEPENDENT OF | THE ACTUAL MANUFACTURED DUT-SPECIFIC BOARD | DESIGN. | TEMPLATE BOARDS DISPLAY AS "FILE VIEWS", AND | DUT-SPECIFIC APPLICATION BOARDS ARE | MANUFACTURED FROM ARTWORK "FILM VIEWS"AND NC | DATA. | AND TITLE BLOCK CONTENT IS TRACKING THE | MANUFACTURED BOARD PART NUMBER AND REV, | AND NOT THE TEMPLATE BOARD PART NUMBER AND | REV. | PAGE 5 OF 5 | MAKE SURE THE DUT-SPECIFIC BOARD INFORMATION | REV.A (20APR20) | 1. INITIAL RELEASE. | REV.B (28MAY20) PER ECR-094468 | 1. BRING FILES INTO TEMPLATE FORMAT.
User.45: 1 | FABRICATION | 09-012345-01 | A | FIGURE | SIZE | 0.254 | 0.264 | 1.143 | 3.175 | DRILL CHART: TOP to BOTTOM | FINISHED HOLES IN MILLIMETERS | PLATED | NON-PLATED | QTY | 205 | 40 | 39 | 2 | 286 | TOLERANCE/NOTES | TOTAL HOLES:
